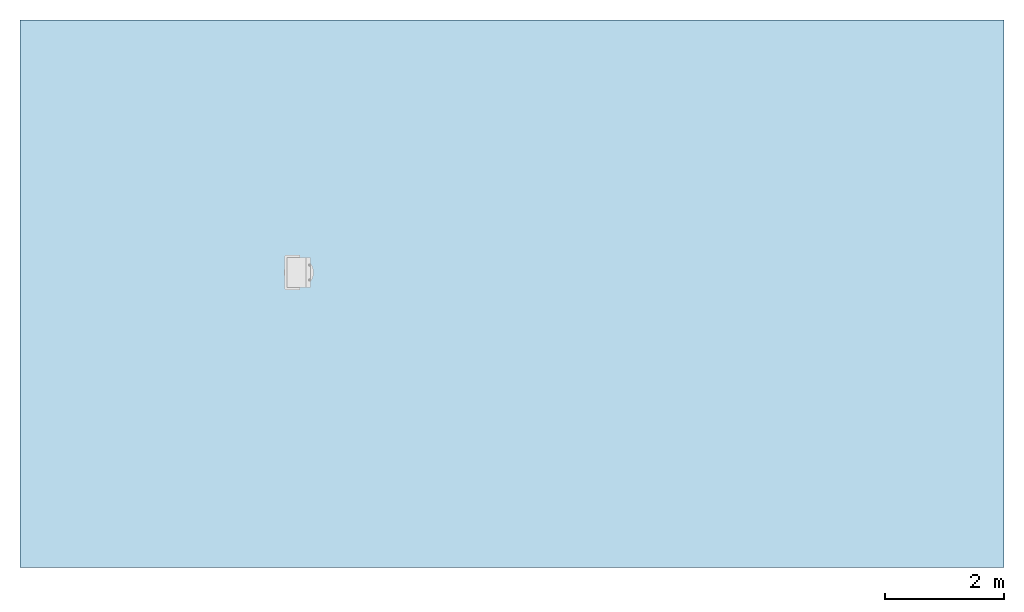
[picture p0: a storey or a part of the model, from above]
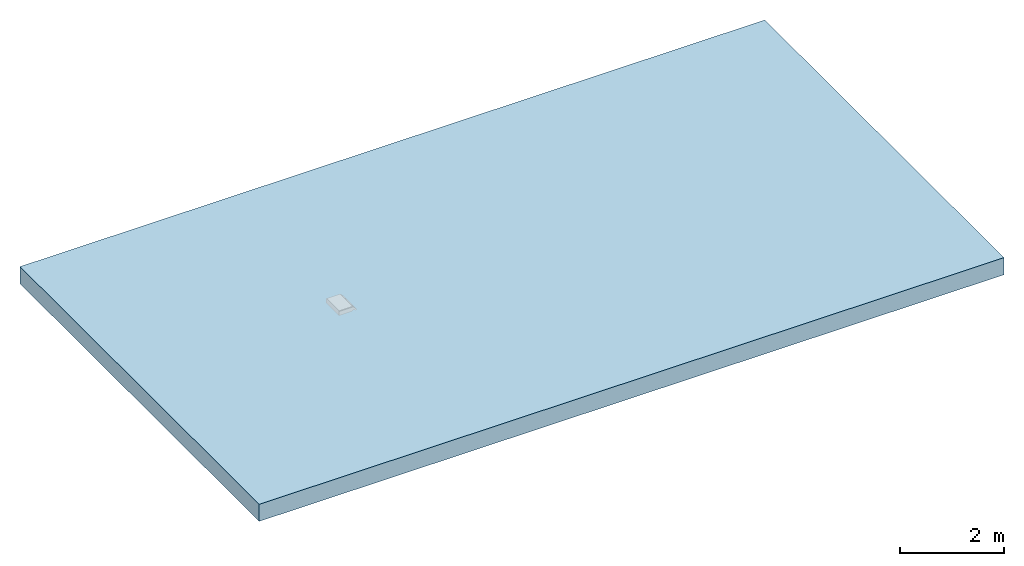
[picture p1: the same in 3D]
Properties of the parts of a building model (IFC2X3)

# File
Description: ViewDefinition [CoordinationView]
Time: 2013-09-04T10:23:05
Written by: Autodesk Revit 2013
Made in: 20120221_2030(x64)

# IfcProject, Project Number
LongName: Project Name; Phase: Project Status

# IfcSite, Default
RefLatitude: 42, 21, 30, 344238; RefLongitude: -71, -3, -35, -194702; RefElevation: 0 mm

# IfcBuilding
Pset_BuildingCommon - NumberOfStoreys: 1
Other - Project Issue Date: Issue Date; Project Number: Project Number; Project Status: Project Status; Project Name: Project Name; Client Name: Owner; Project Address: ## Street City, State Zip

# IfcBuildingStorey, Level 1
LongName: Level 1; Elevation: 0 mm
Constraints - Elevation Base: 0; Elevation: 0 mm
Graphics - Line Pattern: Center; Symbol at End 2 Default: yes; Line Weight: 1; Symbol at End 1 Default: no; Color: 0; Symbol: M_Level Head - Circle: M_Level Head - Circle
Identity Data - Name: Level 1; Building Story: yes; Structural: no
Dimensions - Computation Height: 0 mm

# IfcBuildingElementProxy: 4980 - Top and road gully connector Ø450mm KDSP615, Civil-Drainage-Channel-ACO-KerbDrain-SP Gully unit:4980 - Top and road gully connector Ø450mm KDSP615:4980 - Top and road gully connector Ø450mm KDSP615:312482
In: Level 1
Material: Ductile Iron, ACO Polmer Concrete., Gully
Constraints - Level: Level: Level 1; Moves With Nearby Elements: no
Phasing - Phase Created: New Construction
Dimensions - Volume: 24068691 mm3; Shallow Base Depth: 6000 mm; Top and bottom 4979 void depth: 6000 mm; Deep Base Void Depth: 6000 mm; Gully Connector Void Start: 0 mm; Gully Connector Void End: 40 mm
Pset_BuildingElementProxyCommon - Reference: 4980 - Top and road gully connector Ø450mm KDSP615
Data - Product Standard: BS EN 1433:2002, CE marked, Kitemarked; Installation - Concrete Grade: Refer to brochure; Drainage Slot Width: 50mm; Drainage Slot Intake area: 14592mm²/m; Load Class: A 15 - D 400; Hydraulic Performance: http://www.aco.co.uk/download.php?id=120; ACO Hydraulic Design Software: http://www.acodesign.co.uk; Invert Depth: N/A; Product Dimensions: 500mm x 390mm x 545mm (LxWxH); Product Weight: 81.5 Kg
Identity Data - OmniClass Title: Rainwater Removal; Telephone: +44 (0)1462 816666; OmniClass Number: 23.70.50.24; Maintenance guidelines: http://www.aco.co.uk/download.php?id=120; Assembly Description: Rain Water Drainage; Model: ACO KerbDrain Splayed Gully Units; Installation guidelines: http://www.aco.co.uk/download.php?id=120; Type Comments: ACO KerbDrain Splayed Gully Units - Top & Road Gully Connector Ø450mm KDSP615; e-mail Sales: customersupport@aco.co.uk; Address: ACO Business Park, Hitchin Road, Shefford, Bedfordshire, United Kingdom SG17 5TE; Fax: +44 (0)1462 815895; Price: POA - contact ACO; Cost: 0; Product brochure: http://www.aco.co.uk/download.php?id=120; URL: www.aco.co.uk; Manufacturer: ACO Technologies plc - ACO Water Management Division; Assembly Code: D2040; e-mail Technical: technical@aco.co.uk; Product Page URL: http://www.aco.co.uk/product_detail.php?id=3; Product Code: 4980; Model Description: Combined kerb and drainage system
Other - Revision: 1; CreatedBy: www.aco.co.uk
Materials and Finishes - Gully Cover/Frame Finish: Water Based Paint Coating; Gully Base Material: Vienite® Synthetic Resin Concrete; Gully Base Colour: Brown; Gully Cover/Frame Colour: Black; Gully Cover/Frame Material: Ductile Iron
Green Building Properties - Gully Base Recycled Material Content: 20% minimum; Gully Cover/Frame Recyclable: Fully recyclable; Gully Cover/Frame Recycled Material Content: Between 40% - 90%; Gully Base Recyclable: Fully recyclable
General - TagNumber: 0.000000; SerialNumber: 0.000000
Construction - Top and road gully connector: yes; Shallow base: no; Top and roddable deep base assembly KDSP612RE: no; Top assembly: yes; Deep Base: no

# IfcOpeningElement: Opening (2)
In: Level 1
Constraints - Room Bounding: yes; Level: Level: Level 1; Related to Mass: no; Height Offset From Level: 0 mm
Dimensions - Thickness: 400 mm; Volume: 60509762589 mm3; Perimeter: 51360 mm; Area: 151275000 mm2
Phasing - Phase Created: New Construction
Structural - Enable Analytical Model: no; Structural: no
Construction - Default Thickness: 400 mm; Function: 0
Graphics - Coarse Scale Fill Color: 0
Analytical Properties - Roughness: 1; Absorptance: 0.1
Materials and Finishes - Structural Material: Plant

# IfcSlab: Floor:Generic Floor - 400mm, Floor:Generic Floor - 400mm:193825
In: Level 1
PredefinedType: FLOOR; Material: Plant 400 mm
Constraints - Room Bounding: yes; Level: Level: Level 1; Related to Mass: no; Height Offset From Level: 0 mm
Dimensions - Thickness: 400 mm; Volume: 60509762589 mm3; Perimeter: 51360 mm; Area: 151275000 mm2
Phasing - Phase Created: New Construction
Structural - Enable Analytical Model: no; Structural: no
Pset_SlabCommon - Reference: Generic Floor - 400mm; IsExternal: no; LoadBearing: yes
Construction - Default Thickness: 400 mm; Function: 0
Graphics - Coarse Scale Fill Color: 0
Analytical Properties - Roughness: 1; Absorptance: 0.1
Materials and Finishes - Structural Material: Plant
